VERSION 5.7 ;
  NOWIREEXTENSIONATPIN ON ;
  DIVIDERCHAR "/" ;
  BUSBITCHARS "[]" ;
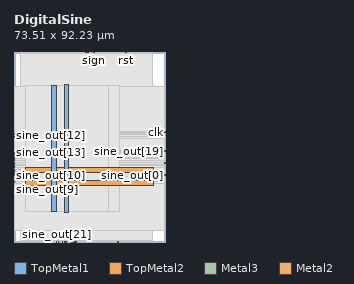
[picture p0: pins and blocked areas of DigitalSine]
MACRO DigitalSine
  CLASS BLOCK ;
  FOREIGN DigitalSine ;
  ORIGIN 0.000 0.000 ;
  SIZE 73.510 BY 92.230 ;
  PIN VGND
    DIRECTION INOUT ;
    USE GROUND ;
    PORT
      LAYER TopMetal1 ;
        RECT 24.460 14.490 26.660 76.230 ;
    END
    PORT
      LAYER TopMetal2 ;
        RECT 5.540 33.820 67.900 36.020 ;
    END
  END VGND
  PIN VPWR
    DIRECTION INOUT ;
    USE POWER ;
    PORT
      LAYER TopMetal1 ;
        RECT 18.260 14.900 20.460 75.820 ;
    END
    PORT
      LAYER TopMetal2 ;
        RECT 5.540 27.620 67.900 29.820 ;
    END
  END VPWR
  PIN clk
    DIRECTION INPUT ;
    USE SIGNAL ;
    ANTENNAGATEAREA 0.725400 ;
    PORT
      LAYER Metal3 ;
        RECT 73.110 53.140 73.510 53.540 ;
    END
  END clk
  PIN rst
    DIRECTION INPUT ;
    USE SIGNAL ;
    ANTENNAGATEAREA 0.180700 ;
    PORT
      LAYER Metal2 ;
        RECT 54.040 91.830 54.440 92.230 ;
    END
  END rst
  PIN sign
    DIRECTION OUTPUT ;
    USE SIGNAL ;
    ANTENNADIFFAREA 0.708600 ;
    PORT
      LAYER Metal2 ;
        RECT 38.680 91.830 39.080 92.230 ;
    END
  END sign
  PIN signB
    DIRECTION OUTPUT ;
    USE SIGNAL ;
    ANTENNADIFFAREA 0.708600 ;
    PORT
      LAYER Metal2 ;
        RECT 34.840 91.830 35.240 92.230 ;
    END
  END signB
  PIN sine_out[0]
    DIRECTION OUTPUT ;
    USE SIGNAL ;
    ANTENNADIFFAREA 0.708600 ;
    PORT
      LAYER Metal3 ;
        RECT 73.110 32.140 73.510 32.540 ;
    END
  END sine_out[0]
  PIN sine_out[10]
    DIRECTION OUTPUT ;
    USE SIGNAL ;
    ANTENNADIFFAREA 0.708600 ;
    PORT
      LAYER Metal3 ;
        RECT 0.000 32.140 0.400 32.540 ;
    END
  END sine_out[10]
  PIN sine_out[11]
    DIRECTION OUTPUT ;
    USE SIGNAL ;
    ANTENNADIFFAREA 0.708600 ;
    PORT
      LAYER Metal3 ;
        RECT 0.000 34.660 0.400 35.060 ;
    END
  END sine_out[11]
  PIN sine_out[12]
    DIRECTION OUTPUT ;
    USE SIGNAL ;
    ANTENNADIFFAREA 0.708600 ;
    PORT
      LAYER Metal3 ;
        RECT 0.000 51.460 0.400 51.860 ;
    END
  END sine_out[12]
  PIN sine_out[13]
    DIRECTION OUTPUT ;
    USE SIGNAL ;
    ANTENNADIFFAREA 0.708600 ;
    PORT
      LAYER Metal3 ;
        RECT 0.000 43.060 0.400 43.460 ;
    END
  END sine_out[13]
  PIN sine_out[14]
    DIRECTION OUTPUT ;
    USE SIGNAL ;
    ANTENNADIFFAREA 0.708600 ;
    PORT
      LAYER Metal3 ;
        RECT 0.000 38.860 0.400 39.260 ;
    END
  END sine_out[14]
  PIN sine_out[15]
    DIRECTION OUTPUT ;
    USE SIGNAL ;
    ANTENNADIFFAREA 0.708600 ;
    PORT
      LAYER Metal3 ;
        RECT 0.000 32.980 0.400 33.380 ;
    END
  END sine_out[15]
  PIN sine_out[16]
    DIRECTION OUTPUT ;
    USE SIGNAL ;
    ANTENNADIFFAREA 0.708600 ;
    PORT
      LAYER Metal3 ;
        RECT 0.000 36.340 0.400 36.740 ;
    END
  END sine_out[16]
  PIN sine_out[17]
    DIRECTION OUTPUT ;
    USE SIGNAL ;
    ANTENNADIFFAREA 0.708600 ;
    PORT
      LAYER Metal3 ;
        RECT 0.000 39.700 0.400 40.100 ;
    END
  END sine_out[17]
  PIN sine_out[18]
    DIRECTION OUTPUT ;
    USE SIGNAL ;
    ANTENNADIFFAREA 0.708600 ;
    PORT
      LAYER Metal3 ;
        RECT 0.000 52.300 0.400 52.700 ;
    END
  END sine_out[18]
  PIN sine_out[19]
    DIRECTION OUTPUT ;
    USE SIGNAL ;
    ANTENNADIFFAREA 0.708600 ;
    PORT
      LAYER Metal3 ;
        RECT 73.110 43.900 73.510 44.300 ;
    END
  END sine_out[19]
  PIN sine_out[1]
    DIRECTION OUTPUT ;
    USE SIGNAL ;
    ANTENNADIFFAREA 0.708600 ;
    PORT
      LAYER Metal3 ;
        RECT 73.110 38.020 73.510 38.420 ;
    END
  END sine_out[1]
  PIN sine_out[20]
    DIRECTION OUTPUT ;
    USE SIGNAL ;
    ANTENNADIFFAREA 0.708600 ;
    PORT
      LAYER Metal2 ;
        RECT 21.400 0.000 21.800 0.400 ;
    END
  END sine_out[20]
  PIN sine_out[21]
    DIRECTION OUTPUT ;
    USE SIGNAL ;
    ANTENNADIFFAREA 0.708600 ;
    PORT
      LAYER Metal2 ;
        RECT 20.440 0.000 20.840 0.400 ;
    END
  END sine_out[21]
  PIN sine_out[22]
    DIRECTION OUTPUT ;
    USE SIGNAL ;
    ANTENNADIFFAREA 0.708600 ;
    PORT
      LAYER Metal3 ;
        RECT 0.000 29.620 0.400 30.020 ;
    END
  END sine_out[22]
  PIN sine_out[23]
    DIRECTION OUTPUT ;
    USE SIGNAL ;
    ANTENNADIFFAREA 0.708600 ;
    PORT
      LAYER Metal3 ;
        RECT 73.110 51.460 73.510 51.860 ;
    END
  END sine_out[23]
  PIN sine_out[24]
    DIRECTION OUTPUT ;
    USE SIGNAL ;
    ANTENNADIFFAREA 0.708600 ;
    PORT
      LAYER Metal3 ;
        RECT 0.000 37.180 0.400 37.580 ;
    END
  END sine_out[24]
  PIN sine_out[25]
    DIRECTION OUTPUT ;
    USE SIGNAL ;
    ANTENNADIFFAREA 0.708600 ;
    PORT
      LAYER Metal3 ;
        RECT 0.000 35.500 0.400 35.900 ;
    END
  END sine_out[25]
  PIN sine_out[26]
    DIRECTION OUTPUT ;
    USE SIGNAL ;
    ANTENNADIFFAREA 0.708600 ;
    PORT
      LAYER Metal2 ;
        RECT 50.200 0.000 50.600 0.400 ;
    END
  END sine_out[26]
  PIN sine_out[27]
    DIRECTION OUTPUT ;
    USE SIGNAL ;
    ANTENNADIFFAREA 0.708600 ;
    PORT
      LAYER Metal2 ;
        RECT 35.800 91.830 36.200 92.230 ;
    END
  END sine_out[27]
  PIN sine_out[28]
    DIRECTION OUTPUT ;
    USE SIGNAL ;
    ANTENNADIFFAREA 0.708600 ;
    PORT
      LAYER Metal2 ;
        RECT 30.040 0.000 30.440 0.400 ;
    END
  END sine_out[28]
  PIN sine_out[29]
    DIRECTION OUTPUT ;
    USE SIGNAL ;
    ANTENNADIFFAREA 0.708600 ;
    PORT
      LAYER Metal2 ;
        RECT 23.320 0.000 23.720 0.400 ;
    END
  END sine_out[29]
  PIN sine_out[2]
    DIRECTION OUTPUT ;
    USE SIGNAL ;
    ANTENNADIFFAREA 0.708600 ;
    PORT
      LAYER Metal3 ;
        RECT 0.000 50.620 0.400 51.020 ;
    END
  END sine_out[2]
  PIN sine_out[30]
    DIRECTION OUTPUT ;
    USE SIGNAL ;
    ANTENNADIFFAREA 0.708600 ;
    PORT
      LAYER Metal2 ;
        RECT 24.280 0.000 24.680 0.400 ;
    END
  END sine_out[30]
  PIN sine_out[31]
    DIRECTION OUTPUT ;
    USE SIGNAL ;
    ANTENNADIFFAREA 0.708600 ;
    PORT
      LAYER Metal2 ;
        RECT 28.120 0.000 28.520 0.400 ;
    END
  END sine_out[31]
  PIN sine_out[32]
    DIRECTION OUTPUT ;
    USE SIGNAL ;
    ANTENNADIFFAREA 0.708600 ;
    PORT
      LAYER Metal2 ;
        RECT 25.240 0.000 25.640 0.400 ;
    END
  END sine_out[32]
  PIN sine_out[3]
    DIRECTION OUTPUT ;
    USE SIGNAL ;
    ANTENNADIFFAREA 0.708600 ;
    PORT
      LAYER Metal3 ;
        RECT 0.000 33.820 0.400 34.220 ;
    END
  END sine_out[3]
  PIN sine_out[4]
    DIRECTION OUTPUT ;
    USE SIGNAL ;
    ANTENNADIFFAREA 0.708600 ;
    PORT
      LAYER Metal3 ;
        RECT 0.000 38.020 0.400 38.420 ;
    END
  END sine_out[4]
  PIN sine_out[5]
    DIRECTION OUTPUT ;
    USE SIGNAL ;
    ANTENNADIFFAREA 0.708600 ;
    PORT
      LAYER Metal3 ;
        RECT 0.000 40.540 0.400 40.940 ;
    END
  END sine_out[5]
  PIN sine_out[6]
    DIRECTION OUTPUT ;
    USE SIGNAL ;
    ANTENNADIFFAREA 0.708600 ;
    PORT
      LAYER Metal3 ;
        RECT 0.000 42.220 0.400 42.620 ;
    END
  END sine_out[6]
  PIN sine_out[7]
    DIRECTION OUTPUT ;
    USE SIGNAL ;
    ANTENNADIFFAREA 0.708600 ;
    PORT
      LAYER Metal3 ;
        RECT 0.000 41.380 0.400 41.780 ;
    END
  END sine_out[7]
  PIN sine_out[8]
    DIRECTION OUTPUT ;
    USE SIGNAL ;
    ANTENNADIFFAREA 0.708600 ;
    PORT
      LAYER Metal2 ;
        RECT 29.080 0.000 29.480 0.400 ;
    END
  END sine_out[8]
  PIN sine_out[9]
    DIRECTION OUTPUT ;
    USE SIGNAL ;
    ANTENNADIFFAREA 0.708600 ;
    PORT
      LAYER Metal3 ;
        RECT 0.000 28.780 0.400 29.180 ;
    END
  END sine_out[9]
  OBS
      LAYER GatPoly ;
        RECT 5.760 14.970 67.680 75.750 ;
      LAYER Metal1 ;
        RECT 5.760 14.900 67.680 75.820 ;
      LAYER Metal2 ;
        RECT 3.255 91.620 34.630 92.080 ;
        RECT 35.450 91.620 35.590 92.080 ;
        RECT 36.410 91.620 38.470 92.080 ;
        RECT 39.290 91.620 53.830 92.080 ;
        RECT 54.650 91.620 67.305 92.080 ;
        RECT 3.255 0.610 67.305 91.620 ;
        RECT 3.255 0.400 20.230 0.610 ;
        RECT 21.050 0.400 21.190 0.610 ;
        RECT 22.010 0.400 23.110 0.610 ;
        RECT 23.930 0.400 24.070 0.610 ;
        RECT 24.890 0.400 25.030 0.610 ;
        RECT 25.850 0.400 27.910 0.610 ;
        RECT 28.730 0.400 28.870 0.610 ;
        RECT 29.690 0.400 29.830 0.610 ;
        RECT 30.650 0.400 49.990 0.610 ;
        RECT 50.810 0.400 67.305 0.610 ;
      LAYER Metal3 ;
        RECT 0.100 53.750 73.110 75.700 ;
        RECT 0.100 52.930 72.900 53.750 ;
        RECT 0.100 52.910 73.110 52.930 ;
        RECT 0.610 52.090 73.110 52.910 ;
        RECT 0.100 52.070 73.110 52.090 ;
        RECT 0.610 51.250 72.900 52.070 ;
        RECT 0.100 51.230 73.110 51.250 ;
        RECT 0.610 50.410 73.110 51.230 ;
        RECT 0.100 44.510 73.110 50.410 ;
        RECT 0.100 43.690 72.900 44.510 ;
        RECT 0.100 43.670 73.110 43.690 ;
        RECT 0.610 42.850 73.110 43.670 ;
        RECT 0.100 42.830 73.110 42.850 ;
        RECT 0.610 42.010 73.110 42.830 ;
        RECT 0.100 41.990 73.110 42.010 ;
        RECT 0.610 41.170 73.110 41.990 ;
        RECT 0.100 41.150 73.110 41.170 ;
        RECT 0.610 40.330 73.110 41.150 ;
        RECT 0.100 40.310 73.110 40.330 ;
        RECT 0.610 39.490 73.110 40.310 ;
        RECT 0.100 39.470 73.110 39.490 ;
        RECT 0.610 38.650 73.110 39.470 ;
        RECT 0.100 38.630 73.110 38.650 ;
        RECT 0.610 37.810 72.900 38.630 ;
        RECT 0.100 37.790 73.110 37.810 ;
        RECT 0.610 36.970 73.110 37.790 ;
        RECT 0.100 36.950 73.110 36.970 ;
        RECT 0.610 36.130 73.110 36.950 ;
        RECT 0.100 36.110 73.110 36.130 ;
        RECT 0.610 35.290 73.110 36.110 ;
        RECT 0.100 35.270 73.110 35.290 ;
        RECT 0.610 34.450 73.110 35.270 ;
        RECT 0.100 34.430 73.110 34.450 ;
        RECT 0.610 33.610 73.110 34.430 ;
        RECT 0.100 33.590 73.110 33.610 ;
        RECT 0.610 32.770 73.110 33.590 ;
        RECT 0.100 32.750 73.110 32.770 ;
        RECT 0.610 31.930 72.900 32.750 ;
        RECT 0.100 30.230 73.110 31.930 ;
        RECT 0.610 29.410 73.110 30.230 ;
        RECT 0.100 29.390 73.110 29.410 ;
        RECT 0.610 28.570 73.110 29.390 ;
        RECT 0.100 5.780 73.110 28.570 ;
      LAYER Metal4 ;
        RECT 5.655 14.975 50.980 75.745 ;
      LAYER Metal5 ;
        RECT 5.615 14.810 45.745 75.910 ;
  END
END DigitalSine
END LIBRARY

